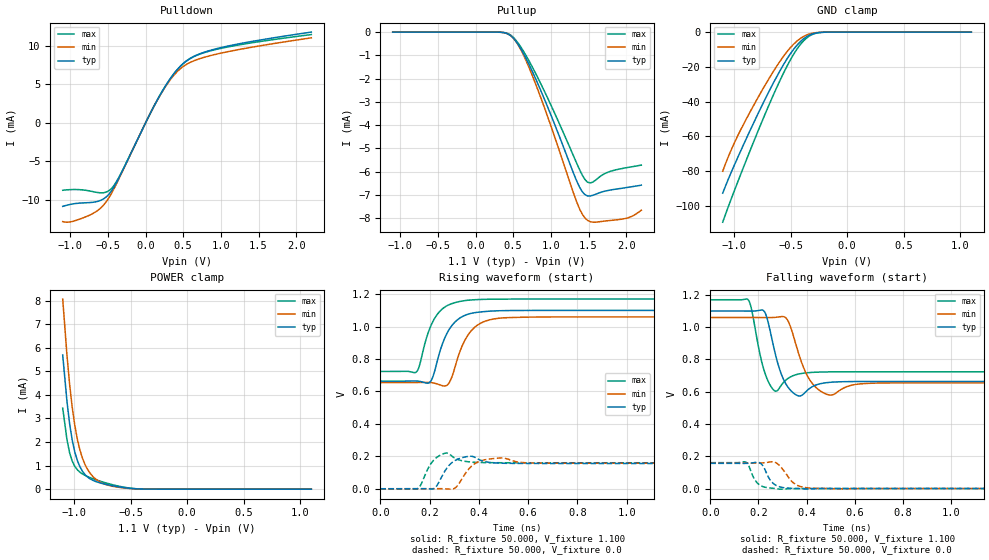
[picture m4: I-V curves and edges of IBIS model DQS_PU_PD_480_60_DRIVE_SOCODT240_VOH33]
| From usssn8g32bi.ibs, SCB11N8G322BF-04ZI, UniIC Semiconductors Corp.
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|   Model DQS_PU_PD_480_60_DRIVE_SOCODT240_VOH33
[Model] DQS_PU_PD_480_60_DRIVE_SOCODT240_VOH33
Model_type I/O
Polarity   Inverting
Vinl =  98.000mV
Vinh =  0.268V
Vmeas =  0.183V
Rref =  50.000
Vref =  0.183V
C_comp   1.020pF   1.010pF   1.030pF
[Model Spec]
Vinh   0.268V   0.262V   0.280V
Vinl   98.000mV   92.000mV   0.110V
Vmeas   0.183V   0.177V   0.195V
Vref   0.183V   0.177V   0.195V
Rref   50.000   NA   NA
[Temperature Range]   25.000   85.000   -40.000
[Voltage Range]   1.100V   1.060V   1.170V
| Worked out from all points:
|   slope of the pulldown table from 0 to 0.165 V, typ, clamps not added: 52.7 ohm
|   GND clamp passes 1 mA (typ) near -0.30 V on its own axis
|   POWER clamp passes 1 mA (typ) near -0.95 V on its own axis
|   rising waveform, R_fixture 50.000, V_fixture 1.100: 20-80 % time 68.7ps typ, 71.5ps min, 66.3ps max; typ from 0.663 V to 1.1 V
|   rising waveform, R_fixture 50.000, V_fixture 0.0: 20-80 % time 34.6ps typ, 42.3ps min, 28.2ps max; typ from 0 V to 0.156 V
|   falling waveform, R_fixture 50.000, V_fixture 1.100: 20-80 % time 42.3ps typ, 53ps min, 33.8ps max; typ from 1.1 V to 0.663 V
|   falling waveform, R_fixture 50.000, V_fixture 0.0: 20-80 % time 37.3ps typ, 51.4ps min, 33.8ps max; typ from 0.156 V to 0 V
[Pulldown]
|Voltage   I(typ)   I(min)   I(max)
-1.1V     -10.83mA   -12.81mA   -8.746mA
-964mV    -10.51mA   -12.77mA   -8.65mA
-692mV    -10.29mA   -11.72mA   -8.932mA
-556mV    -9.849mA   -10.65mA   -9.063mA
-454mV    -8.849mA   -9.178mA   -8.534mA
-318mV    -6.436mA   -6.525mA   -6.383mA
158mV     3.005mA    2.979mA    3.019mA
328mV     5.729mA    5.594mA    5.734mA
498mV     7.686mA    7.305mA    7.672mA
668mV     8.751mA    8.153mA    8.715mA
940mV     9.618mA    8.913mA    9.532mA
2.2V      11.78mA    11.03mA    11.45mA
[Pullup]
|Voltage   I(typ)   I(min)   I(max)
-1.1V     500pA      2.606nA    0A
296mV     -2.948uA   -3.529uA   -1.641uA
466mV     -154.8uA   -152.1uA   -129.1uA
602mV     -725.8uA   -765uA     -649.5uA
738mV     -1.585mA   -1.746mA   -1.41mA
976mV     -3.374mA   -3.816mA   -2.972mA
1.316V    -6.198mA   -7.072mA   -5.446mA
1.452V    -6.989mA   -7.995mA   -6.341mA
1.52V     -7.049mA   -8.152mA   -6.489mA
1.724V    -6.835mA   -8.124mA   -6.072mA
1.928V    -6.723mA   -8.051mA   -5.878mA
2.2V      -6.582mA   -7.66mA    -5.721mA
[GND_clamp]
|Voltage   I(typ)   I(min)   I(max)
-1.1V     -92.78mA   -80.14mA   -109.5mA
-1.031V   -81.73mA   -68.77mA   -97.17mA
-939mV    -68.18mA   -56.07mA   -81.64mA
-801mV    -48.85mA   -39.25mA   -59.15mA
-663mV    -30.71mA   -23.84mA   -37.89mA
-571mV    -19.76mA   -14.75mA   -24.85mA
-479mV    -10.5mA    -7.415mA   -13.5mA
-410mV    -5.313mA   -3.546mA   -6.916mA
-341mV    -2.007mA   -1.262mA   -2.59mA
-272mV    -506.9uA   -323.5uA   -609.8uA
-180mV    -45.65uA   -36.06uA   -43.55uA
1.1V      0A         0A         0A
[POWER_clamp]
|Voltage   I(typ)   I(min)   I(max)
-1.1V     5.691mA    8.066mA    3.44mA
-1.062V   3.709mA    5.665mA    2.092mA
-1.039V   2.781mA    4.457mA    1.546mA
-1.016V   2.086mA    3.48mA     1.193mA
-993mV    1.578mA    2.707mA    966.5uA
-970mV    1.21mA     2.107mA    818.5uA
-924mV    750.8uA    1.296mA    641.3uA
-878mV    507uA      821.4uA    530.2uA
-809mV    327.4uA    430uA      403.3uA
-694mV    178.4uA    161uA      233uA
-464mV    19.89uA    15.19uA    23.61uA
1.1V      0A         0A         0A
[Ramp]
| variable   typ   min   max
dV/dt_r   93.600m/34.547p   94.432m/42.426p   96.210m/28.300p
dV/dt_f   0.262/42.313p   0.243/53.004p   0.268/33.830p
R_load = 50.000
[Rising Waveform]
R_fixture= 50.000
V_fixture= 1.100
V_fixture_min= 1.060
V_fixture_max= 1.170
|time   V(typ)   V(min)   V(max)
0s        663.5mV    654.8mV    723.5mV
146ps     664.5mV    655.2mV    719.7mV
159ps     662.5mV    655.7mV    759.6mV
200ps     655.3mV    655.6mV    985.1mV
233ps     797.6mV    645.6mV    1.079V
275ps     970.8mV    644.1mV    1.132V
354ps     1.075V     943.5mV    1.162V
420ps     1.092V     1.03V      1.168V
540ps     1.099V     1.056V     1.17V
3ns       1.1V       1.06V      1.17V
[Rising Waveform]
R_fixture= 50.000
V_fixture= 0.0
V_fixture_min= 0.0
V_fixture_max= 0.0
|time   V(typ)   V(min)   V(max)
0s        3.261uV    6.245uV    770.5nV
154ps     200.8uV    8.722uV    3.43mV
220ps     3.031mV    385.2uV    181.4mV
266ps     117.7mV    -555.6uV   220.1mV
308ps     177.8mV    10.32mV    184.8mV
358ps     200.1mV    119.7mV    166.4mV
403ps     178.2mV    169.6mV    162mV
491ps     157.7mV    190.1mV    160.5mV
643ps     156mV      157.9mV    160.3mV
3ns       156mV      157.4mV    160.3mV
[Falling Waveform]
R_fixture= 50.000
V_fixture= 1.100
V_fixture_min= 1.060
V_fixture_max= 1.170
|time   V(typ)   V(min)   V(max)
0s        1.1V       1.06V      1.17V
158ps     1.1V       1.06V      1.169V
227ps     1.091V     1.06V      716mV
272ps     823.2mV    1.061V     602.9mV
320ps     634.4mV    1.046V     679.4mV
357ps     580mV      886.2mV    705.8mV
414ps     621.8mV    671.4mV    718.9mV
496ps     658mV      579.1mV    722.9mV
685ps     663.4mV    653.2mV    723.5mV
3ns       663.5mV    654.8mV    723.5mV
[Falling Waveform]
R_fixture= 50.000
V_fixture= 0.0
V_fixture_min= 0.0
V_fixture_max= 0.0
|time   V(typ)   V(min)   V(max)
0s        156mV      157.4mV    160.3mV
147ps     155.8mV    157.2mV    163.9mV
185ps     161.3mV    157mV      54.63mV
202ps     161.1mV    157.4mV    25.74mV
219ps     139.7mV    159.1mV    11.89mV
255ps     41.26mV    165.3mV    2.438mV
292ps     9.086mV    135mV      -4.025mV
353ps     836.9uV    26.65mV    -453.5uV
438ps     -1.078mV   1.237mV    -10.83uV
3ns       3.161uV    6.116uV    477.7nV
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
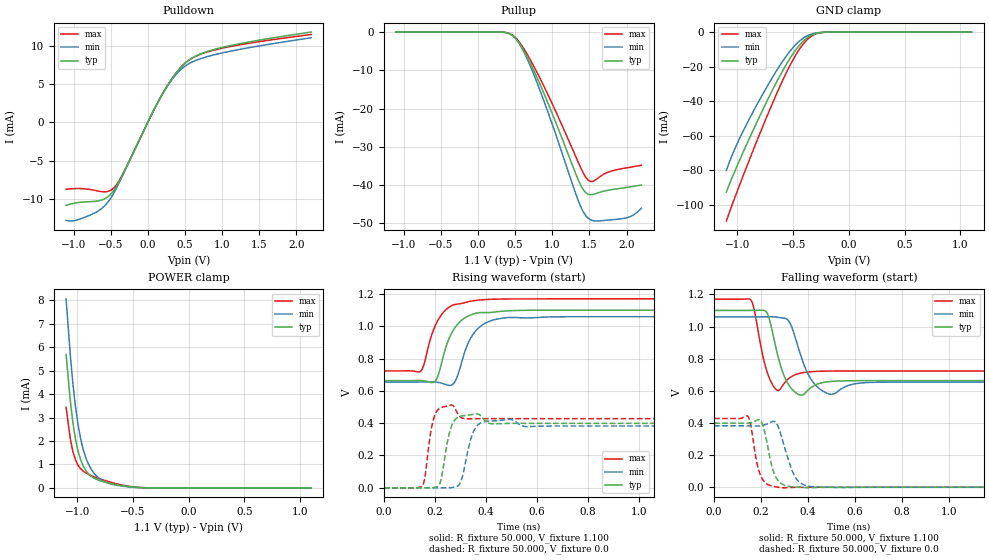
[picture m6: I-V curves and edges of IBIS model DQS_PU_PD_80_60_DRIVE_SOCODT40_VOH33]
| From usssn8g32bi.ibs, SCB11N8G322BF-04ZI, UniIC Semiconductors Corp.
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|   Model DQS_PU_PD_80_60_DRIVE_SOCODT40_VOH33
[Model] DQS_PU_PD_80_60_DRIVE_SOCODT40_VOH33
Model_type I/O
Polarity   Inverting
Vinl =  98.000mV
Vinh =  0.268V
Vmeas =  0.183V
Rref =  50.000
Vref =  0.183V
C_comp   1.020pF   1.010pF   1.030pF
[Model Spec]
Vinh   0.268V   0.262V   0.280V
Vinl   98.000mV   92.000mV   0.110V
Vmeas   0.183V   0.177V   0.195V
Vref   0.183V   0.177V   0.195V
Rref   50.000   NA   NA
[Temperature Range]   25.000   85.000   -40.000
[Voltage Range]   1.100V   1.060V   1.170V
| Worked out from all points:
|   slope of the pulldown table from 0 to 0.165 V, typ, clamps not added: 52.7 ohm
|   GND clamp passes 1 mA (typ) near -0.30 V on its own axis
|   POWER clamp passes 1 mA (typ) near -0.95 V on its own axis
|   rising waveform, R_fixture 50.000, V_fixture 1.100: 20-80 % time 66.2ps typ, 66.8ps min, 65.2ps max; typ from 0.663 V to 1.1 V
|   rising waveform, R_fixture 50.000, V_fixture 0.0: 20-80 % time 25.8ps typ, 32.7ps min, 20.8ps max; typ from 0 V to 0.399 V
|   falling waveform, R_fixture 50.000, V_fixture 1.100: 20-80 % time 43.2ps typ, 54.9ps min, 34.3ps max; typ from 1.1 V to 0.663 V
|   falling waveform, R_fixture 50.000, V_fixture 0.0: 20-80 % time 38.1ps typ, 51.9ps min, 33.4ps max; typ from 0.399 V to 0 V
[Pulldown]
|Voltage   I(typ)   I(min)   I(max)
-1.1V     -10.83mA   -12.81mA   -8.746mA
-964mV    -10.51mA   -12.77mA   -8.65mA
-692mV    -10.29mA   -11.72mA   -8.932mA
-556mV    -9.849mA   -10.65mA   -9.063mA
-454mV    -8.849mA   -9.178mA   -8.534mA
-318mV    -6.436mA   -6.525mA   -6.383mA
158mV     3.005mA    2.979mA    3.019mA
328mV     5.729mA    5.594mA    5.734mA
498mV     7.686mA    7.305mA    7.672mA
668mV     8.751mA    8.153mA    8.715mA
940mV     9.618mA    8.913mA    9.532mA
2.2V      11.78mA    11.03mA    11.45mA
[Pullup]
|Voltage   I(typ)   I(min)   I(max)
-1.1V     3.1nA      15.54nA    0A
296mV     -17.69uA   -21.17uA   -9.843uA
466mV     -927.4uA   -911uA     -773.6uA
602mV     -4.341mA   -4.574mA   -3.886mA
738mV     -9.474mA   -10.43mA   -8.429mA
976mV     -20.15mA   -22.77mA   -17.76mA
1.35V     -38.63mA   -44.04mA   -34.05mA
1.452V    -42.01mA   -48.04mA   -38mA
1.554V    -42.45mA   -49.35mA   -39mA
1.928V    -40.84mA   -48.83mA   -35.77mA
2.064V    -40.44mA   -48.15mA   -35.29mA
2.2V      -40mA      -46.05mA   -34.84mA
[GND_clamp]
|Voltage   I(typ)   I(min)   I(max)
-1.1V     -92.78mA   -80.14mA   -109.5mA
-1.031V   -81.73mA   -68.77mA   -97.17mA
-939mV    -68.18mA   -56.07mA   -81.64mA
-801mV    -48.85mA   -39.25mA   -59.15mA
-663mV    -30.71mA   -23.84mA   -37.89mA
-571mV    -19.76mA   -14.75mA   -24.85mA
-479mV    -10.5mA    -7.415mA   -13.5mA
-410mV    -5.313mA   -3.546mA   -6.916mA
-341mV    -2.007mA   -1.262mA   -2.59mA
-272mV    -506.9uA   -323.5uA   -609.8uA
-180mV    -45.65uA   -36.06uA   -43.55uA
1.1V      0A         0A         0A
[POWER_clamp]
|Voltage   I(typ)   I(min)   I(max)
-1.1V     5.691mA    8.066mA    3.44mA
-1.062V   3.709mA    5.665mA    2.092mA
-1.039V   2.781mA    4.457mA    1.546mA
-1.016V   2.086mA    3.48mA     1.193mA
-993mV    1.578mA    2.707mA    966.5uA
-970mV    1.21mA     2.107mA    818.5uA
-924mV    750.8uA    1.296mA    641.3uA
-878mV    507uA      821.4uA    530.2uA
-809mV    327.4uA    430uA      403.3uA
-694mV    178.4uA    161uA      233uA
-464mV    19.89uA    15.19uA    23.61uA
1.1V      0A         0A         0A
[Ramp]
| variable   typ   min   max
dV/dt_r   0.239/26.065p   0.230/32.804p   0.257/21.150p
dV/dt_f   0.262/43.228p   0.243/54.887p   0.268/34.368p
R_load = 50.000
[Rising Waveform]
R_fixture= 50.000
V_fixture= 1.100
V_fixture_min= 1.060
V_fixture_max= 1.170
|time   V(typ)   V(min)   V(max)
0s        663.5mV    654.8mV    723.5mV
145ps     664.4mV    655.3mV    723.7mV
196ps     654.3mV    655.8mV    984.1mV
213ps     698.6mV    652.6mV    1.041V
267ps     961.8mV    637.9mV    1.129V
286ps     1.008V     682.6mV    1.137V
333ps     1.066V     904.6mV    1.153V
374ps     1.085V     994.1mV    1.163V
491ps     1.096V     1.055V     1.169V
3ns       1.1V       1.06V      1.17V
[Rising Waveform]
R_fixture= 50.000
V_fixture= 0.0
V_fixture_min= 0.0
V_fixture_max= 0.0
|time   V(typ)   V(min)   V(max)
0s        3.261uV    6.245uV    770.5nV
152ps     -211.2uV   51.84uV    14.27mV
161ps     -234.6uV   50.72uV    69.49mV
187ps     295.3uV    11.15uV    375.6mV
214ps     11.8mV     -169.2uV   486.5mV
261ps     362.4mV    713.2uV    512.4mV
303ps     444.3mV    44.17mV    435.1mV
356ps     456.8mV    363mV      427.7mV
408ps     401.4mV    412.6mV    428.2mV
3ns       398.9mV    382.6mV    428.3mV
[Falling Waveform]
R_fixture= 50.000
V_fixture= 1.100
V_fixture_min= 1.060
V_fixture_max= 1.170
|time   V(typ)   V(min)   V(max)
0s        1.1V       1.06V      1.17V
157ps     1.1V       1.06V      1.165V
225ps     1.086V     1.061V     720.9mV
273ps     809.5mV    1.057V     601.8mV
318ps     636.5mV    1.034V     676.8mV
359ps     577.5mV    866.8mV    706.5mV
413ps     620.4mV    670.9mV    718.9mV
494ps     657.7mV    579.1mV    722.8mV
695ps     663.4mV    653.5mV    723.5mV
3ns       663.5mV    654.8mV    723.5mV
[Falling Waveform]
R_fixture= 50.000
V_fixture= 0.0
V_fixture_min= 0.0
V_fixture_max= 0.0
|time   V(typ)   V(min)   V(max)
0s        398.9mV    382.6mV    428.3mV
144ps     398.1mV    381.9mV    440.5mV
155ps     400.9mV    381.6mV    393.7mV
197ps     416.3mV    382.6mV    77.07mV
212ps     363.3mV    387.3mV    38.23mV
253ps     96.15mV    410.3mV    5.795mV
287ps     22.29mV    315.3mV    -2.96mV
344ps     2.127mV    66.91mV    -604.2uV
418ps     -2.215mV   3.841mV    -22.75uV
3ns       1.67uV     6.173uV    -1.494uV
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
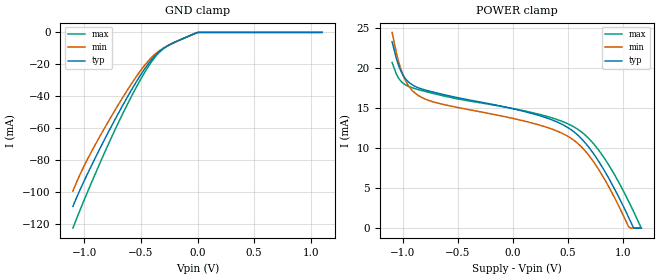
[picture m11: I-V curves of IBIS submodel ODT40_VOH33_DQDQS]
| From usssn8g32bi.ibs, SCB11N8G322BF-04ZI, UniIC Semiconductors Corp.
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|   Submodel ODT40_VOH33_DQDQS
[Submodel] ODT40_VOH33_DQDQS
Submodel_type Dynamic_clamp
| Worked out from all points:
|   GND clamp passes 1 mA (typ) near -0.03 V on its own axis
[GND_clamp]
|Voltage   I(typ)   I(min)   I(max)
-1.1V     -108.9mA   -99.29mA   -122.5mA
-1.008V   -94.06mA   -84.59mA   -106.2mA
-916mV    -80.48mA   -71.99mA   -90.73mA
-755mV    -58.1mA    -51.9mA    -65.05mA
-617mV    -40.2mA    -35.88mA   -44.75mA
-525mV    -29.22mA   -26.14mA   -32.31mA
-433mV    -19.58mA   -17.79mA   -21.26mA
-364mV    -13.83mA   -12.99mA   -14.56mA
-295mV    -9.767mA   -9.567mA   -9.91mA
-203mV    -6.239mA   -6.263mA   -6.231mA
4mV       0A         0A         0A
1.1V      0A         0A         0A
[POWER_clamp]
|Voltage   I(typ)   I(min)   I(max)
-1.1V     23.32mA    24.5mA     20.73mA
-1.039V   20.28mA    20.76mA    18.72mA
-993mV    18.98mA    18.9mA     18.06mA
-924mV    18mA       17.34mA    17.6mA
-855mV    17.53mA    16.55mA    17.31mA
226mV     14.15mA    12.96mA    14.29mA
456mV     12.94mA    11.82mA    13.32mA
594mV     11.61mA    10.57mA    12.35mA
801mV     7.942mA    6.913mA    9.398mA
1.054V    1.365mA    179.9uA    3.373mA
1.1V      0A         0A         2.072mA
1.17V     0A         0A         0A
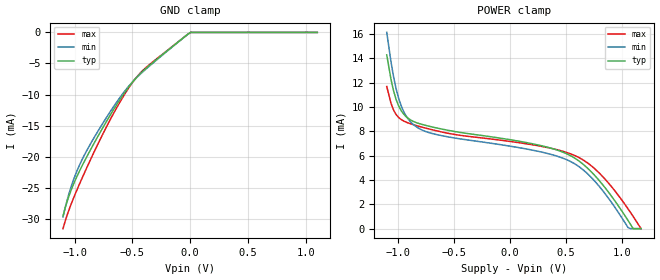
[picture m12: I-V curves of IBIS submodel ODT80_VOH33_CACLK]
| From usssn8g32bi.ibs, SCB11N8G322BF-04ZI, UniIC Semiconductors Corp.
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|   Submodel ODT80_VOH33_CACLK
[Submodel] ODT80_VOH33_CACLK
Submodel_type Dynamic_clamp
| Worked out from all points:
|   GND clamp passes 1 mA (typ) near -0.07 V on its own axis
[GND_clamp]
|Voltage   I(typ)   I(min)   I(max)
-1.1V     -29.53mA   -29.68mA   -31.58mA
-1.031V   -25.44mA   -24.9mA    -27.69mA
-985mV    -23.41mA   -22.55mA   -25.59mA
-939mV    -21.62mA   -20.63mA   -23.62mA
-847mV    -18.37mA   -17.44mA   -19.87mA
-732mV    -14.59mA   -13.93mA   -15.49mA
-548mV    -9.204mA   -9.034mA   -9.407mA
-456mV    -7.102mA   -7.156mA   -7.051mA
-387mV    -5.867mA   -5.976mA   -5.742mA
-19mV     -282uA     -284.5uA   -278.5uA
4mV       0A         0A         0A
1.1V      0A         0A         0A
[POWER_clamp]
|Voltage   I(typ)   I(min)   I(max)
-1.1V     14.29mA    16.14mA    11.69mA
-1.039V   11.33mA    12.49mA    9.749mA
-993mV    10.08mA    10.69mA    9.13mA
-924mV    9.181mA    9.213mA    8.745mA
-855mV    8.788mA    8.501mA    8.527mA
-625mV    8.221mA    7.677mA    7.982mA
272mV     6.837mA    6.317mA    6.781mA
594mV     5.704mA    5.238mA    5.945mA
801mV     3.909mA    3.432mA    4.537mA
1.054V    671.8uA    89.49uA    1.629mA
1.1V      0A         0A         1.001mA
1.17V     0A         0A         0A
